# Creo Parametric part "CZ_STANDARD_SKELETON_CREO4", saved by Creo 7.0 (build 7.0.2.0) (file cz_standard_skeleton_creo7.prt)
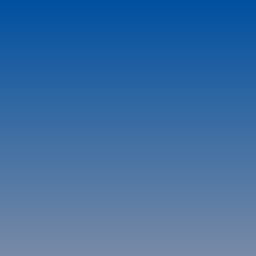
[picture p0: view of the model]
Units: Custom; MM, KILOGRAM, SECS

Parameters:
  BEARBEITER = "."
  ERSTELLUNGSDATUM = "."
  KONSTRUKTIONSGRUPPE = "."
  ZEICHNUNGSNUMMER = "CZ_STANDARD_SKE/ET"
  TEILDOKUMENT = "002"
  VERSION = "01"
  KOMP_STUFE = "T"
  KOMP_CHAR = "M"
  BENENNUNG = "Skelettmodell"
  KENNWORT = "HT"
  PTC_COMMON_NAME = "cz_standard_skeleton_creo7.prt"

Other parameters: PREIS

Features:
  1. datum plane "Y-Z"
  2. datum plane "X-Z"
  3. datum plane "X-Y"
  4. coordinate system
  5. datum axis
  6. datum axis
  7. datum axis

Other named items: X0Y0Z0, X-ACHSE, Y-ACHSE, Z-ACHSE

Layers: ACHSEN, EBENEN, FLAECHEN, GEWINDE, KOORDSYS, KURVEN, PUNKTE, RUNDUNGEN, S_ACHSEN, S_EBENEN, S_KOORDSYS, VERBFLAECHE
